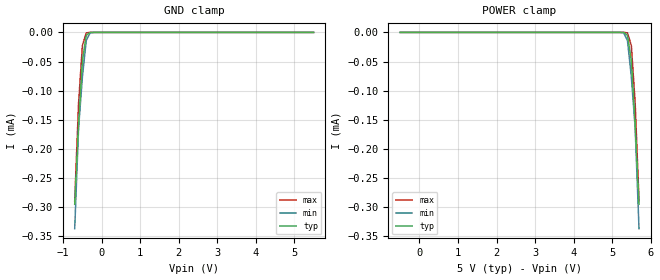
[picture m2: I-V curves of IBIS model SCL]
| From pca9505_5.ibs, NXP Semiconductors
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[Model]   SCL
Model_type Input
Vinh=3.5
Vinl=1.5
C_comp   3.4p   3.2p   3.6p
[Temperature Range] 27   85   -40
[Voltage Range]   5   4.5   5.5
[GND Clamp]
-700mV    -295uA     -337uA     -289.5uA
-600mV    -158.8uA   -164.3uA   -122uA
-500mV    -48.62uA   -75.94uA   -22.35uA
-400mV    -4.926uA   -13.83uA   -710.6nA
-300mV    -138.4nA   -722.3nA   -7.551nA
5.5V      13.38pA    37.84pA    11.03pA
[POWER Clamp]
-500mV    13.38pA    37.84pA    11.03pA
5.3V      -138.4nA   -722.3nA   -7.551nA
5.4V      -4.926uA   -13.83uA   -710.6nA
5.5V      -48.62uA   -75.94uA   -22.35uA
5.6V      -158.8uA   -164.3uA   -122uA
5.7V      -295uA     -337uA     -289.5uA
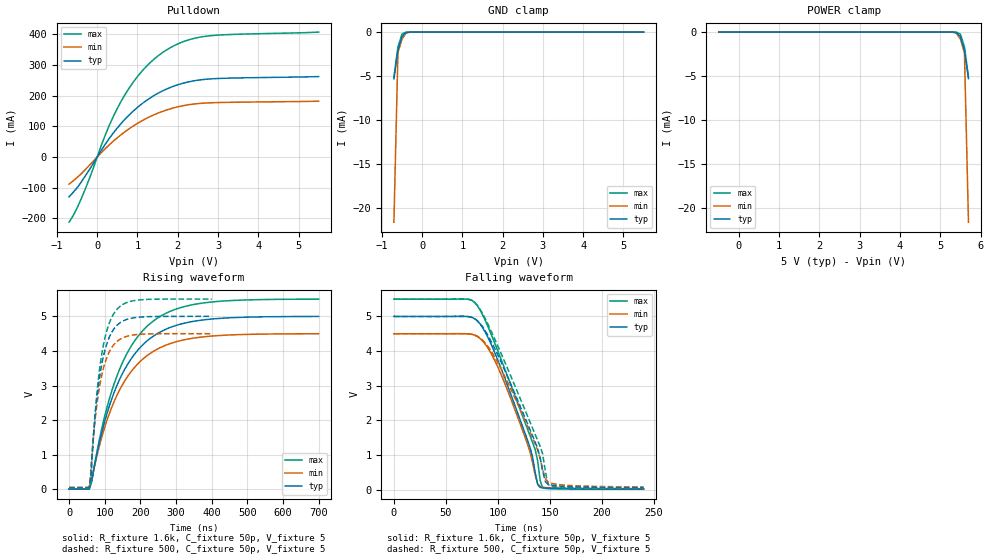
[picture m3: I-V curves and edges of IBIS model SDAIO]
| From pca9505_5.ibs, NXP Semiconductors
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[Model]   SDAIO
Model_type I/O_open_drain
Vinh=3.5
Vinl=1.5
Vref=5
Vmeas=2.5
Rref=1.6k
Cref=50p
C_comp   7p   6.8p   7.2p
[Temperature Range] 27   85   -40
[Voltage Range]   5   4.5   5.5
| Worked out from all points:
|   slope of the pulldown table from 0 to 0.75 V, typ, clamps not added: 5.73 ohm
|   GND clamp passes 1 mA (typ) near -0.53 V on its own axis
|   falling waveform, R_fixture 1.6k, C_fixture 50p, V_fixture 5: 20-80 % time 36.4ns typ, 33.3ns min, 41.5ns max; typ from 5 V to 0.016 V
|   falling waveform, R_fixture 500, C_fixture 50p, V_fixture 5: 20-80 % time 41.6ns typ, 39.1ns min, 45.8ns max; typ from 5 V to 0.052 V
|   rising waveform, R_fixture 1.6k, C_fixture 50p, V_fixture 5: 20-80 % time 113ns typ, 113ns min, 113ns max; typ from 0.014 V to 5 V
|   rising waveform, R_fixture 500, C_fixture 50p, V_fixture 5: 20-80 % time 35.4ns typ, 35.5ns min, 35.3ns max; typ from 0.046 V to 5 V
[Pulldown]
-700mV    -130.1mA   -88.65mA   -212.3mA
-600mV    -115.7mA   -78.13mA   -191.9mA
-400mV    -82.42mA   -55.14mA   -137.2mA
-200mV    -42.7mA    -28.06mA   -72.72mA
200mV     41.52mA    27.01mA    71.22mA
500mV     94.47mA    62.55mA    158.1mA
700mV     124.2mA    83.05mA    205mA
1V        161.3mA    109.3mA    261.7mA
1.5V      206.6mA    142.3mA    327.9mA
2V        234.9mA    163.1mA    367.8mA
2.6V      251.6mA    174.8mA    391mA
5.5V      261.7mA    181.5mA    406.4mA
[GND Clamp]
-700mV    -5.302mA   -21.58mA   -5.122mA
-600mV    -2.04mA    -2.358mA   -1.687mA
-500mV    -525.2uA   -816.9uA   -228.9uA
-400mV    -48.21uA   -135uA     -7.763uA
-200mV    -27.28nA   -200nA     -811.9pA
5.5V      106.9pA    399pA      72.28pA
[POWER Clamp]
-500mV    106.9pA    399pA      72.28pA
5.2V      -27.28nA   -200nA     -811.9pA
5.4V      -48.21uA   -135uA     -7.763uA
5.5V      -525.2uA   -816.9uA   -228.9uA
5.6V      -2.04mA    -2.358mA   -1.687mA
5.7V      -5.302mA   -21.58mA   -5.122mA
[Falling Waveform]
R_fixture=1.6k
C_fixture=50p
V_fixture=5
V_fixture_min=4.5
V_fixture_max=5.5
0s        5V         4.5V       5.5V
80ns      4.875V     4.425V     5.319V
92.12ns   4.285V     4.002V     4.585V
104.2ns   3.403V     3.237V     3.666V
130.9ns   1.213V     1.078V     1.549V
135.8ns   506.1mV    416.2mV    1.157V
138.2ns   145.2mV    164.6mV    829.3mV
140.6ns   60.72mV    85.35mV    259.2mV
143ns     46.87mV    64.84mV    46.73mV
240ns     16.06mV    22.78mV    10.03mV
[Falling Waveform]
R_fixture=500
C_fixture=50p
V_fixture=5
V_fixture_min=4.5
V_fixture_max=5.5
0s        5V         4.5V       5.5V
70.3ns    4.998V     4.499V     5.499V
80ns      4.884V     4.43V      5.33V
89.7ns    4.492V     4.16V      4.818V
101.8ns   3.76V      3.556V     4.014V
140.6ns   922.7mV    887.2mV    1.241V
143ns     521.8mV    575.8mV    1.019V
145.5ns   229.1mV    322.7mV    547.4mV
147.9ns   157.9mV    224mV      153.4mV
240ns     52.07mV    73.77mV    32.47mV
[Rising Waveform]
R_fixture=1.6k
C_fixture=50p
V_fixture=5
V_fixture_min=4.5
V_fixture_max=5.5
0s        14.24mV    19.93mV    8.968mV
56.57ns   13.11mV    23.84mV    8.968mV
63.64ns   266mV      286.7mV    219mV
98.99ns   1.924V     1.759V     2.072V
134.3ns   3.004V     2.719V     3.278V
176.8ns   3.813V     3.439V     4.18V
233.3ns   4.406V     3.969V     4.841V
297ns     4.728V     4.256V     5.199V
374.7ns   4.895V     4.406V     5.384V
700ns     4.998V     4.498V     5.498V
[Rising Waveform]
R_fixture=500
C_fixture=50p
V_fixture=5
V_fixture_min=4.5
V_fixture_max=5.5
0s        45.6mV     63.66mV    28.76mV
56.57ns   46.66mV    85.93mV    28.76mV
60.61ns   311.3mV    446.8mV    110.3mV
72.73ns   2.078V     1.971V     2.132V
80.81ns   2.87V      2.655V     3.047V
88.89ns   3.448V     3.155V     3.714V
105.1ns   4.176V     3.785V     4.554V
129.3ns   4.682V     4.223V     5.135V
189.9ns   4.971V     4.474V     5.466V
400ns     5V         4.5V       5.5V
[Ramp]
R_load=1.6k
dV/dt_r   2.992E+0/2.552E-9   2.987E+0/2.863E-9   2.995E+0/2.273E-9
dV/dt_f   2.991E+0/3.625E-8   2.985E+0/3.633E-8   2.995E+0/3.770E-8
|[End   SDAIO
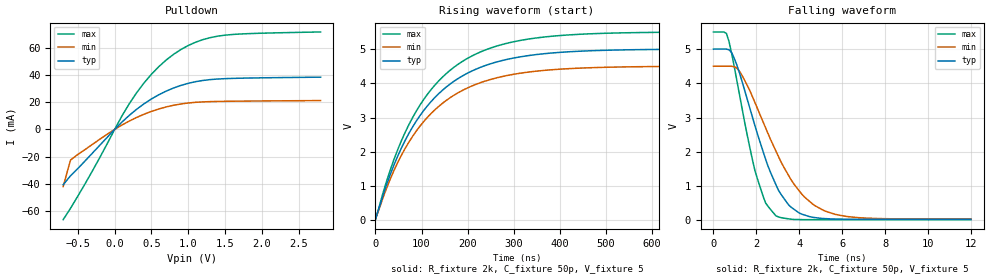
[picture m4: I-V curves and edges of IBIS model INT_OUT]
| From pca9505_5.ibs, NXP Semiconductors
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[Model]   INT_OUT
Model_type Open_drain
Vref=5
Vmeas=2.5
Rref=2k
Cref=50p
C_comp   5.2p   5p   5.4p
[Temperature Range] 27   85   -40
[Voltage Range]   5   4.5   5.5
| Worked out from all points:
|   slope of the pulldown table from 0 to 0.75 V, typ, clamps not added: 25.7 ohm
|   falling waveform, R_fixture 2k, C_fixture 50p, V_fixture 5: 20-80 % time 1.57ns typ, 2.09ns min, 1.11ns max; typ from 5 V to 0.027 V
|   rising waveform, R_fixture 2k, C_fixture 50p, V_fixture 5: 20-80 % time 141ns typ, 141ns min, 141ns max; typ from 0.027 V to 5 V
[Pulldown]
-700mV    -40.51mA   -41.9mA    -66.09mA
-600mV    -33.94mA   -22.43mA   -57.78mA
-500mV    -28.63mA   -18.29mA   -48.81mA
-200mV    -11.46mA   -7.098mA   -20.4mA
100mV     5.434mA    3.245mA    9.958mA
300mV     14.82mA    8.837mA    26.97mA
500mV     22.32mA    13.24mA    40.43mA
800mV     30.35mA    17.7mA     54.98mA
1.1V      34.99mA    19.87mA    63.89mA
1.4V      36.94mA    20.52mA    68.32mA
1.8V      37.64mA    20.78mA    70.14mA
2.8V      38.3mA     21.15mA    71.4mA
[Falling Waveform]
R_fixture=2k
C_fixture=50p
V_fixture=5
V_fixture_min=4.5
V_fixture_max=5.5
0s        5V         4.5V       5.5V
606.1ps   5V         4.5V       5.455V
1.091ns   4.536V     4.444V     4.086V
1.939ns   2.754V     3.432V     1.439V
2.424ns   1.798V     2.71V      516.1mV
2.909ns   1.043V     2.027V     133.9mV
4ns       211.8mV    859mV      21.45mV
5.212ns   48.86mV    267.2mV    17.71mV
7.152ns   27.95mV    62.47mV    17.65mV
12ns      27.36mV    37.56mV    17.65mV
[Rising Waveform]
R_fixture=2k
C_fixture=50p
V_fixture=5
V_fixture_min=4.5
V_fixture_max=5.5
0s        27.36mV    37.48mV    17.65mV
40.4ns    1.62V      1.459V     1.783V
64.65ns   2.336V     2.103V     2.572V
88.89ns   2.901V     2.61V      3.194V
113.1ns   3.347V     3.011V     3.685V
145.5ns   3.797V     3.416V     4.18V
210.1ns   4.364V     3.926V     4.803V
282.8ns   4.689V     4.219V     5.16V
387.9ns   4.89V      4.4V       5.379V
800ns     4.998V     4.498V     5.498V
[Ramp]
R_load=2k
dV/dt_r   2.981E+0/2.424E-9   2.970E+0/2.677E-9   2.990E+0/2.145E-9
dV/dt_f   2.984E+0/1.239E-10   2.975E+0/1.753E-10   2.990E+0/1.190E-10
|[End   INT_OUT
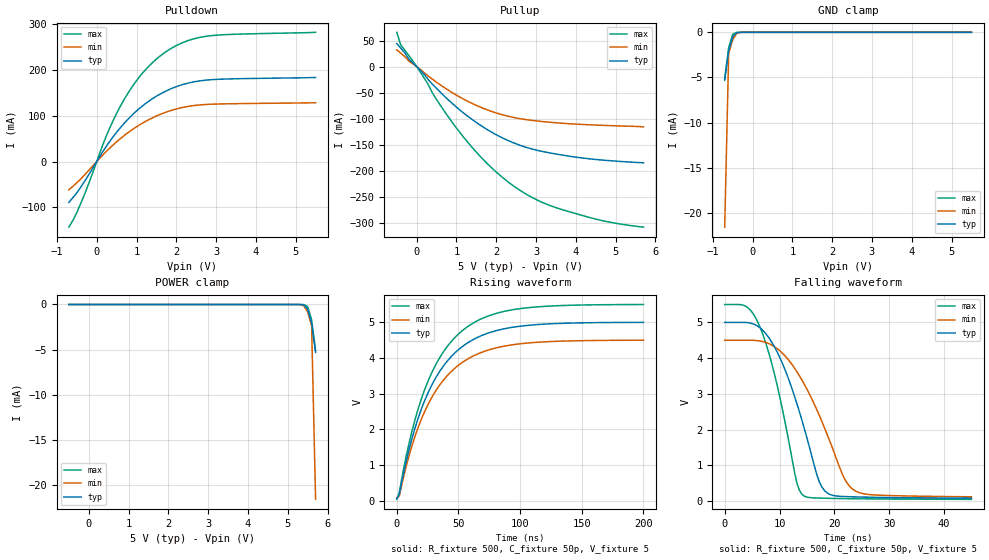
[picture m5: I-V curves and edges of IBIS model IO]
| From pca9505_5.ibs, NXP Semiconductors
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[Model]   IO
Model_type I/O
Vinh=3.5
Vinl=1.5
Vref=5
Vmeas=2.5
Rref=500
Cref=50p
C_comp   7p   6.8p   7.2p
[Temperature Range] 27   85   -40
[Voltage Range]   5   4.5   5.5
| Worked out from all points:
|   slope of the pulldown table from 0 to 0.75 V, typ, clamps not added: 8.45 ohm
|   slope of the pullup table from 0 to 0.75 V, typ, clamps not added: 12.4 ohm
|   GND clamp passes 1 mA (typ) near -0.53 V on its own axis
|   falling waveform, R_fixture 500, C_fixture 50p, V_fixture 5: 20-80 % time 6.17ns typ, 7.67ns min, 4.82ns max; typ from 5 V to 0.084 V
|   rising waveform, R_fixture 500, C_fixture 50p, V_fixture 5: 20-80 % time 36.1ns typ, 36.3ns min, 35.9ns max; typ from 0.069 V to 5 V
[Pullup]
-500mV    44.37mA    32.24mA    65.95mA
-400mV    35.62mA    25.85mA    41.66mA
-200mV    14.71mA    10.98mA    21.46mA
200mV     -15.8mA    -12.62mA   -23.36mA
500mV     -42.05mA   -30.02mA   -63.32mA
900mV     -71.22mA   -50.33mA   -107.9mA
1.5V      -107.6mA   -74.59mA   -164.6mA
2.2V      -138.8mA   -93.59mA   -215.9mA
2.8V      -156.3mA   -102.5mA   -247.5mA
3.5V      -168.1mA   -108mA     -271.3mA
4.6V      -179.3mA   -112.7mA   -295.1mA
5.7V      -185.1mA   -116mA     -308.8mA
[Pulldown]
-700mV    -88.82mA   -61.44mA   -142.8mA
-600mV    -78.73mA   -54.01mA   -128.4mA
-400mV    -55.68mA   -37.91mA   -90.96mA
200mV     27.79mA    18.42mA    46.69mA
400mV     52.47mA    35.15mA    86.88mA
600mV     74.24mA    50.22mA    121.3mA
800mV     93.34mA    63.67mA    150.8mA
1.1V      117.4mA    80.99mA    187mA
1.6V      147.1mA    102.7mA    230.1mA
2.1V      165.8mA    116.5mA    256.4mA
2.7V      176.7mA    123.9mA    271.8mA
5.5V      182.8mA    127.9mA    281.1mA
[GND Clamp]
-700mV    -5.302mA   -21.58mA   -5.122mA
-600mV    -2.04mA    -2.358mA   -1.687mA
-500mV    -525.2uA   -816.9uA   -228.9uA
-400mV    -48.21uA   -135uA     -7.763uA
-200mV    -27.28nA   -200nA     -811.9pA
5.5V      106.9pA    399pA      72.28pA
[POWER Clamp]
-500mV    106.9pA    399pA      72.28pA
5.2V      -27.28nA   -200nA     -811.9pA
5.4V      -48.21uA   -135uA     -7.763uA
5.5V      -525.2uA   -816.9uA   -228.9uA
5.6V      -2.04mA    -2.358mA   -1.687mA
5.7V      -5.302mA   -21.58mA   -5.122mA
[Falling Waveform]
R_fixture=500
C_fixture=50p
V_fixture=5
V_fixture_min=4.5
V_fixture_max=5.5
0s        5V         4.5V       5.5V
4.091ns   4.994V     4.5V       5.428V
6.364ns   4.858V     4.482V     4.896V
10.45ns   3.879V     4.148V     2.624V
13.18ns   2.722V     3.619V     500.1mV
14.55ns   2.019V     3.263V     138.2mV
18.18ns   299.1mV    2.06V      82.72mV
21.82ns   130.1mV    641.5mV    71.97mV
23.64ns   120.4mV    303.5mV    68.34mV
45ns      84.14mV    122.7mV    51.79mV
[Rising Waveform]
R_fixture=500
C_fixture=50p
V_fixture=5
V_fixture_min=4.5
V_fixture_max=5.5
0s        68.84mV    93.97mV    44.49mV
2.02ns    175.9mV    136.9mV    227.2mV
6.061ns   866.3mV    749.2mV    986.5mV
12.12ns   1.723V     1.522V     1.926V
24.24ns   2.94V      2.623V     3.261V
38.38ns   3.802V     3.405V     4.202V
54.55ns   4.356V     3.909V     4.804V
72.73ns   4.681V     4.207V     5.157V
98.99ns   4.885V     4.394V     5.377V
200ns     4.998V     4.498V     5.498V
[Ramp]
R_load=500
dV/dt_r   1.455E-2/2.110E-9   1.306E-2/2.471E-9   1.621E-2/1.589E-9
dV/dt_f   2.950E+0/3.593E-9   2.628E+0/4.670E-9   3.269E+0/2.815E-9
|[End   IO
